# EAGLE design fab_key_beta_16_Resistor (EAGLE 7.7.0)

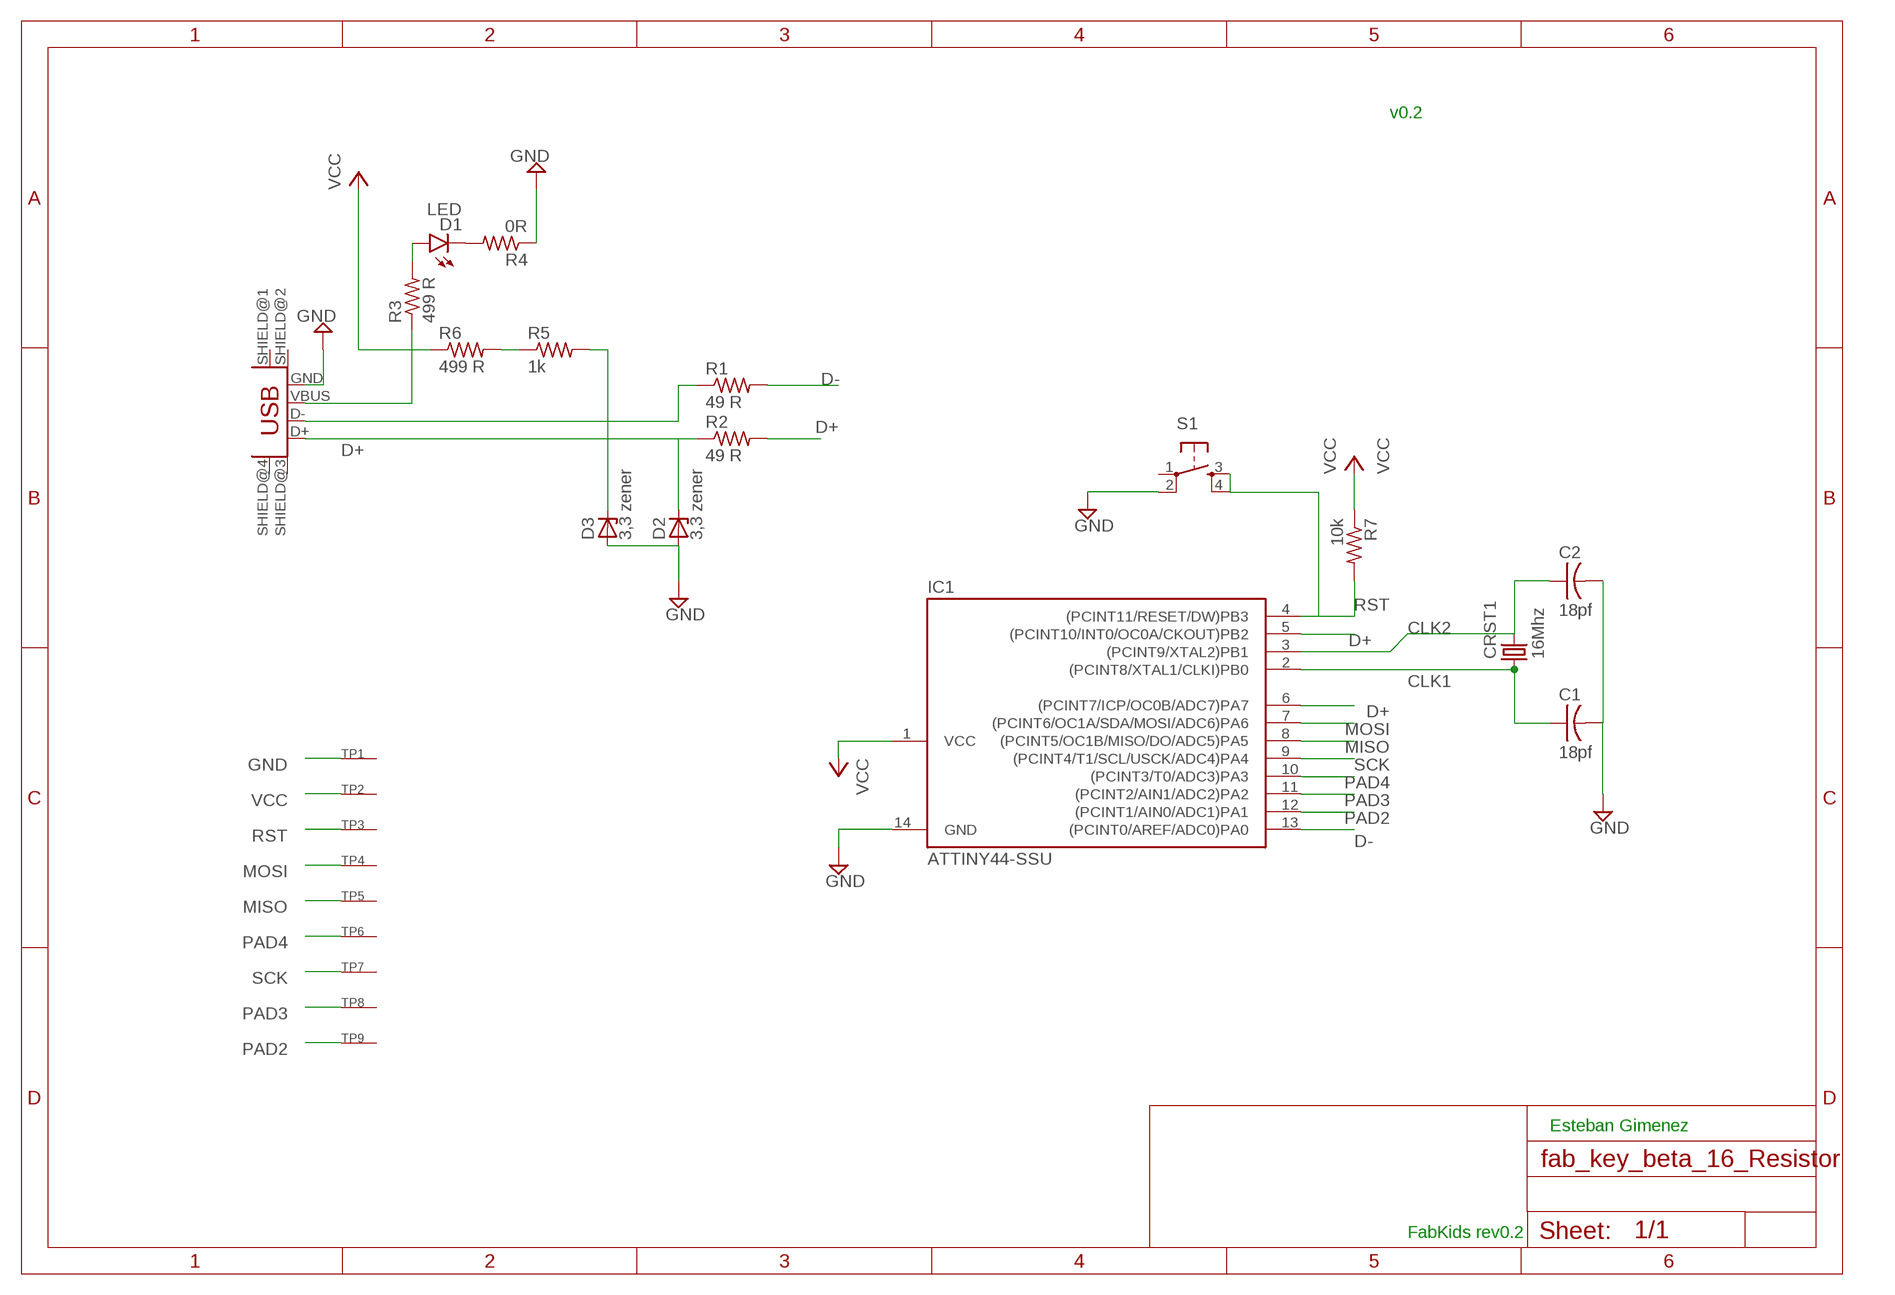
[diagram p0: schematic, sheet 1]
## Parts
C1  18pf  CAP-US1206FAB  [C1206FAB]
C2  18pf  CAP-US1206FAB  [C1206FAB]
CRST1  16Mhz  CRYSTAL  [2-SMD-5X3MM]
D1  LED  LED1206  [LED-1206]
D2  3,3 zener  ZENER_DIODESOD123  [SOD123]
D3  3,3 zener  ZENER_DIODESOD123  [SOD123]
IC1  ATTINY44-SSU  [SOIC14]
MINIUSB  USB_MINIB  [USB_MINIB]
R1  49 R  RES-US1206FAB  [R1206FAB]
R2  49 R  RES-US1206FAB  [R1206FAB]
R3  499 R  RES-US1206FAB  [R1206FAB]
R4  0R  RES-US1206FAB  [R1206FAB]
R5  1k  RES-US1206FAB  [R1206FAB]
R6  499 R  RES-US1206FAB  [R1206FAB]
R7  10k  RES-US1206FAB  [R1206FAB]
S1  6MM_SWITCH6MM_SWITCH  [6MM_SWITCH]
TP1  SEWTAPBIG  [BIGTAP]
TP2  SEWTAPBIG  [BIGTAP]
TP3  SEWTAPBIG  [BIGTAP]
TP4  SEWTAPBIG  [BIGTAP]
TP5  SEWTAPBIG  [BIGTAP]
TP6  SEWTAPBIG  [BIGTAP]
TP7  SEWTAPBIG  [BIGTAP]
TP8  SEWTAPBIG  [BIGTAP]
TP9  SEWTAPBIG  [BIGTAP]

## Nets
CLK1: C1.1 CRST1.P$1 IC1.2((PCINT8/XTAL1/CLKI)PB0)
CLK2: C2.1 CRST1.P$2 IC1.3((PCINT9/XTAL2)PB1)
D+: D2.CATHODE IC1.5((PCINT10/INT0/OC0A/CKOUT)PB2) IC1.6((PCINT7/ICP/OC0B/ADC7)PA7) MINIUSB.D+ R2.1 R2.2
D-: D3.CATHODE IC1.13((PCINT0/AREF/ADC0)PA0) MINIUSB.D- R1.1 R1.2 R5.2
GND: C1.2 C2.2 D2.ANODE D3.ANODE IC1.14(GND) MINIUSB.GND R4.1 S1.2(P1) TP1.P$1(SEW)
MISO: IC1.8((PCINT5/OC1B/MISO/DO/ADC5)PA5) TP5.P$1(SEW)
MOSI: IC1.7((PCINT6/OC1A/SDA/MOSI/ADC6)PA6) TP4.P$1(SEW)
N$2: D1.C R4.2
N$8: D1.A R3.2
N$9: R5.1 R6.2
PAD2: IC1.12((PCINT1/AIN0/ADC1)PA1) TP9.P$1(SEW)
PAD3: IC1.11((PCINT2/AIN1/ADC2)PA2) TP8.P$1(SEW)
PAD4: IC1.10((PCINT3/T0/ADC3)PA3) TP6.P$1(SEW)
RST: IC1.4((PCINT11/RESET/DW)PB3) R7.2 S1.3(S) S1.4(S1) TP3.P$1(SEW)
SCK: IC1.9((PCINT4/T1/SCL/USCK/ADC4)PA4) TP7.P$1(SEW)
VCC: IC1.1(VCC) MINIUSB.VBUS R3.1 R6.1 R7.1 TP2.P$1(SEW)
Unconnected: MINIUSB.SHIELD@1(SHIELD) MINIUSB.SHIELD@2(SHIELD1) MINIUSB.SHIELD@3(SHIELD2) MINIUSB.SHIELD@4(SHIELD3) S1.1(P)

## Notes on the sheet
- v0.2
- Esteban Gimenez
- FabKids rev0.2

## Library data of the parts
C1 C2 = fab:CAP-US
CRST1 = fab:CRYSTAL
D1 = SparkFun-LED:LED: LEDs
D2 D3 = fab:ZENER_DIODE: zener diode
IC1 = fab:ATTINY44
MINIUSB = fab:USB_MINIB
R1-R7 = fab:RES-US: Resistor (US Symbol)
S1 = fab:6MM_SWITCH: OMRON SWITCH
TP1-TP9 = adafruit:SEWTAP

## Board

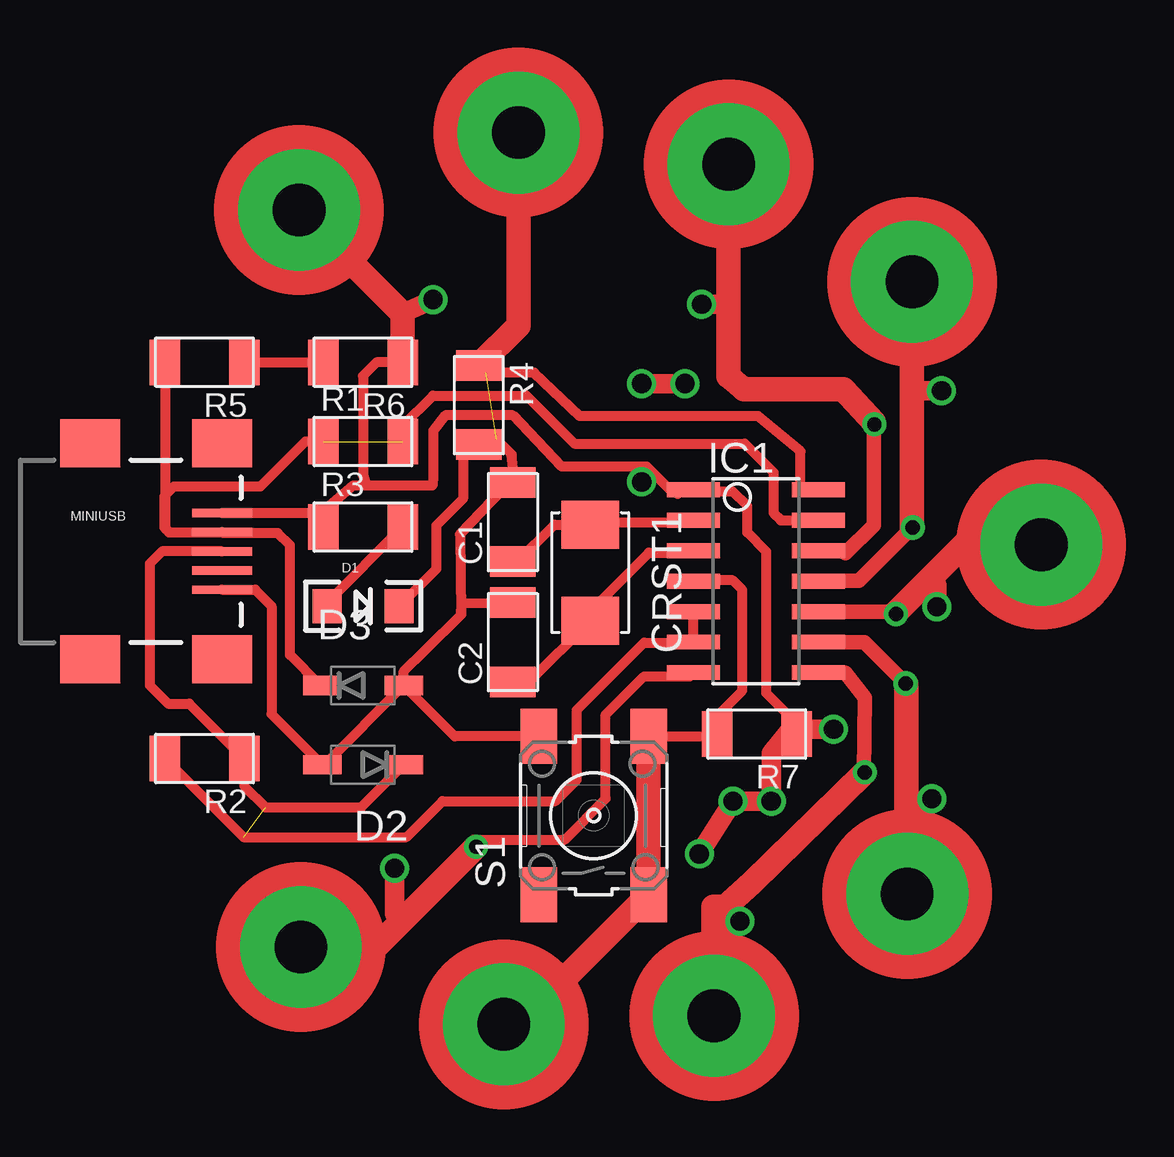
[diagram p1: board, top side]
No outline drawn. Coordinates in mm, seen from the top.
Copper layers (1*16): Top 0.035mm / dielectric 1.5mm / Bottom 0.035mm
Design rules "board12_1_3_5v": minimum track width 10mil, minimum drill 24mil, track to track 16mil, track to pad 0.205mm, pad to pad 0.205mm, via to via 0.205mm, smd to smd 6mil, copper to edge 40mil, drill to drill 8mil, minimum pad ring 10mil, minimum via ring 8mil, stop-mask expansion 4mil, vias tented up to drill 0mil, thermal gap 10mil

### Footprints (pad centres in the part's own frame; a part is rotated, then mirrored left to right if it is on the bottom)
C1206FAB = smd 1.27 x 1.905: 1 -1.651,0; 2 1.651,0
2-SMD-5X3MM = smd 2 x 2.4: P$1 -2,0; P$2 2,0
LED-1206 = smd 1.2 x 1.4: A -1.5,0; C 1.5,0
SOD123 = smd 1.6 x 0.8: ANODE 1.7,0; CATHODE -1.7,0
SOIC14 = smd 0.61 x 2.21: 1 -3.81,-2.603; 2 -2.54,-2.603; 3 -1.27,-2.603; 4 0,-2.603; 5 1.27,-2.603; 6 2.54,-2.603; 7 3.81,-2.603; 8 3.81,2.603; 9 2.54,2.603; 10 1.27,2.603; 11 0,2.603; 12 -1.27,2.603; 13 -2.54,2.603; 14 -3.81,2.603
USB_MINIB = smd 2.5 x 0.35: D+ 3.77,0; D- 3.77,0.8; GND 3.77,-1.6; ID 3.77,-0.8; VBUS 3.77,1.6 | smd 2.5 x 2: SHIELD@1 -1.73,-4.5; SHIELD@2 -1.73,4.5; SHIELD@3 3.77,4.5; SHIELD@4 3.77,-4.5
R1206FAB = smd 1.27 x 1.905: 1 -1.651,0; 2 1.651,0
6MM_SWITCH = smd 2.286 x 1.524: 1 -3.302,2.286; 2 3.302,2.286; 3 -3.302,-2.286; 4 3.302,-2.286
BIGTAP = drill 2.2 pad 5.08: P$1 0,0

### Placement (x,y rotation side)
C1  20.63,22.53 90 top
C2  20.63,17.52 90 top
CRST1  23.86,20.42 270 top
D1  14.38,19.02 0 top
D2  14.38,12.42 180 top
D3  14.38,15.72 0 top
IC1  30.77,20.06 270 top
MINIUSB  4.73,21.31 0 top
R1  14.38,25.88 0 top
R2  7.78,12.67 180 top
R3  14.38,22.32 0 top
R4  19.21,27.4 270 top
R5  7.78,29.18 180 top
R6  14.38,29.18 180 top
R7  30.8,13.7 180 top
S1  24,10.3 90 top
TP1  20.86,38.76 0 top
TP2  11.72,35.53 0 top
TP3  20.25,1.6 0 top
TP4  11.79,4.82 0 top
TP5  29.01,1.95 0 top
TP6  42.66,21.59 0 top
TP7  37.07,7.03 0 top
TP8  37.27,32.53 0 top
TP9  29.62,37.44 0 top

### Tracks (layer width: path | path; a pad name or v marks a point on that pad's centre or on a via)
CLK1
  Top 0.406: C1.1 20.81,20.88 22.36,22.43 CRST1.P$1 24.87,22.42 24.98,22.53 28.09,22.53 IC1.2
CLK2
  Top 0.406: C2.1 21.31,15.87 CRST1.P$2 23.86,18.82 26.3,21.26 28.09,21.26 IC1.3
D+  (1 unrouted)
  Top 0.406: IC1.5 IC1.6 28.14,17.5 26.1,17.5 23.3,14.7 23.3,11.8 22.4,10.9 17.7,10.9 16.2,9.4 9.4,9.4 R2.2 | MINIUSB.D+ 6,21.31 5.49,20.8 5.49,15.72 6.26,14.96 7.14,14.96 R2.1 9.43,11.53 10.32,10.64 14.31,10.64 D2.CATHODE
D-  (1 unrouted)
  Top 0.406: D3.CATHODE 12.61,15.72 11.34,16.99 11.34,21.56 10.83,22.07 8.54,22.07 MINIUSB.D- 6.3,22.1 | R1.2 16.04,26.54 17.3,27.8 21.2,27.8 23.2,25.8 30.3,25.8 31.5,24.6 31.5,22.9 31.8,22.6 IC1.13 | R5.2 6.13,22.27 6.3,22.1 | R1.1 11.98,25.88 10.1,24 6.5,24 6.1,23.6 6.1,22.3 6.3,22.1 | 6.3,22.1 MINIUSB.D-
GND  (1 unrouted)
  Top 0.406: D3.ANODE 12.78,12.42 D2.ANODE 10.57,14.53 10.57,19.02 9.89,19.71 MINIUSB.GND | D3.ANODE 16.08,16.3 16.98,17.19 18.47,18.67 | 18.47,18.67 18.5,19.15 C2.2 | C1.2 20.68,24.38 | 20.68,24.38 18.42,22.02 18.47,18.67 | 20.68,24.38 20.58,25.35 19.95,25.98 | IC1.14 32.62,23.87 32.62,25.47 30.85,26.94 23.42,26.94 21.52,28.75 19.52,28.75 R4.1 | S1.2 18.2,13.6 D3.ANODE
  Top 1.016: TP1.P$1 20.86,30.71 R4.1
MISO
  Top 0.406: 29,1.97 TP5.P$1
  Top 0.61: IC1.8 34.5,16.25 35.3,15.2 35.27,12.07
  Top 1.016: 35.27,12.07 30.6,7.5 29.5,6.5 29,6.5 29,1.97
MOSI
  Top 0.406: 19,8.9 19,9.3 22.8,9.3 24.5,11 24.5,14.5 26.1,16.1 28.01,16.1 IC1.7
  Top 0.813: 15.7,8.1 15.7,6.2 16,5.9
  Top 1.016: TP4.P$1 14.92,4.82 16,5.9 19,8.9
N$1  (via drill 0.6)
  other vias: 19.1,9
N$2
  Top 0.406: R4.2 18.55,25.73 18.55,23.49 17.43,22.38 17.43,20.57 D1.C
N$3  (via drill 0.6)
  other vias: 35.3,12.1
N$4  (via drill 0.6)
  other vias: 37,15.8
N$5  (via drill 0.6)
  other vias: 35.7,26.6
N$6  (via drill 0.6)
  other vias: 37.3,22.3
N$7  (via drill 0.6)
  other vias: 36.6,18.7
N$8
  Top 0.406: D1.A 12.86,19.02 12.86,19.15 R3.2
N$9
  Top 0.406: R5.1 R6.2
N$10  (via drill 0.8)
  other vias: 28.5,31.6
N$11  (via drill 0.8)
  Top 0.813: v38.5,28 37.2,28 37.3,26.6
N$12  (via drill 0.8)
  Top 0.813: v38.3,19 38.3,19.9 38,20.2
N$13  (via drill 0.8)
  other vias: 38.1,11
N$14
  Top 0.813: 38,10.9 37.1,10.9
N$15  (via drill 0.8)
  other vias: 15.7,8.1
N$16  (via drill 0.8)
  Top 0.813: v17.3,31.8 16,31.2 15.6,31.6
N$18
  Top 0.813: 28.6,31.6 29.3,31.6 29.6,31.3
N$19  (via drill 0.8)
  other vias: 30.1,5.9
N$20
  Top 0.813: 30,5.8 29.1,5.8
N$21  (via drill 0.8)
  Top 0.813: 31.4,12.9 32.3,14 | v28.4,8.7 v29.8,10.9 v31.4,10.9 31.4,12.9 | 31.4,12.9 32.3,13.9 v34,13.9
N$23  (via drill 0.8)
  other vias: 26,28.3
N$24  (via drill 0.8)
  Top 0.813: 26,28.3 v27.8,28.3
N$25  (via drill 0.8)
  other vias: 26,24.2
N$26
  Top 0.813: 26,24.1 26.1,24.6
PAD2
  Top 0.406: 34.5,21.23 33.47,21.23 IC1.12
  Top 0.61: 35.67,26.69 35.67,22.4 34.5,21.23
  Top 1.016: TP9.P$1 29.62,28.6 30.26,28.06 34.4,28.06 35.67,26.69
PAD3
  Top 0.406: 33.38,20.08 IC1.11
  Top 0.61: 37.27,22.29 35.06,20.08 33.38,20.08
  Top 1.016: TP8.P$1 37.27,22.29
PAD4
  Top 0.406: 42.6,21.65 TP6.P$1
  Top 0.61: IC1.10 36.63,18.79
  Top 1.016: 36.63,18.79 39.49,21.65 42.6,21.65
RST
  Top 0.406: S1.4 29.05,13.6 R7.2 29.15,14.45 30.2,15.5 30.2,19.7 29.8,20.1 28.2,20.1 IC1.4
  Top 1.016: TP3.P$1 20.89,1.6 S1.3 S1.4
SCK
  Top 0.406: 37.04,7.06 TP7.P$1
  Top 0.61: IC1.9 35.29,17.52 37.04,15.77
  Top 1.016: 37.04,15.77 37.04,7.06
VCC
  Top 0.406: MINIUSB.VBUS 12.15,22.91 12.38,22.68 | 12.38,22.68 R3.1 | 14.51,24.05 17.28,24.05 17.3,24.41 17.3,26.34 17.81,26.97 20.64,26.97 22.67,24.84 26.22,24.84 27.19,23.87 27.33,23.87 27.5,23.7 27.5,23.8 28.09,23.8 IC1.1 28.24,23.8 29.8,23.8 30.4,23.2 30.4,22.1 31.2,21.3 31.2,15.4 32.45,14.15 R7.1 | 14.51,24.05 13.98,24.05 12.38,22.68 | R6.1 14.94,29.18 14.38,28.62 14.38,24.46 14.51,24.05
  Top 1.016: TP2.P$1 16.04,31.21 R6.1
